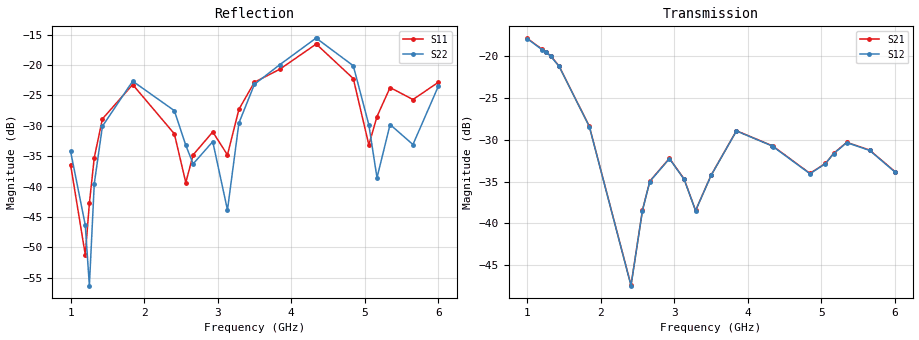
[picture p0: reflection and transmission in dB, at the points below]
!Agilent Technologies,E8364B,MY43040528,A.07.50.67
!Agilent E8364B: A.07.50.67
!Date: Sunday, March 01, 2026 22:01:33
!Correction: S11(Full 2 Port(1,2))
!S21(Full 2 Port(1,2))
!S12(Full 2 Port(1,2))
!S22(Full 2 Port(1,2))
!S2P File: Measurements: S11, S21, S12, S22:
# Hz S  dB  R 50
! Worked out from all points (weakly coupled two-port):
!   451 points, 1 GHz to 6 GHz, reference 50 ohm
!   highest |S21| = -17.88 dB at 1 GHz (marker M1); lowest = -47.4 dB at 2.411 GHz (marker M2)
!   lowest |S11| = -51.2 dB at 1.2 GHz (marker M3), VSWR 1.01, Z = 50.1 - j0.244 ohm
!   |S11| at or under -10 dB: start of sweep to end of sweep
!   |S22| runs from -61.2 to -15.6 dB; largest |S21 - S12| = 0.00051
!   S11 on the Smith chart (normalised r, x): 1 GHz: 1.03, +0.01; 4.333 GHz: 1.23, -0.24; 6 GHz: 0.98, -0.14
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1e9  -36.38 17.3  -17.88 28.8  -17.92 28.9  -34.18 -28.7
1.2e9  -51.20 -62.2  -19.18 -31.3  -19.22 -31.3  -46.32 -34.0
1.255556e9  -42.75 -129.8  -19.50 -49.2  -19.54 -49.2  -56.28 -177.4
1.322222e9  -35.21 -153.7  -20.00 -71.4  -20.04 -71.3  -39.50 128.3
1.433333e9  -28.85 174.5  -21.20 -108.7  -21.23 -108.7  -30.05 95.0
1.844444e9  -23.21 83.4  -28.40 121.9  -28.43 122.0  -22.65 -14.1
2.411111e9  -31.31 5.6  -47.38 -127.2  -47.44 -127.2  -27.50 -123.5
2.566667e9  -39.32 37.0  -38.42 108.8  -38.46 108.9  -33.19 -139.6
2.666667e9  -34.76 71.8  -34.95 63.8  -34.99 63.8  -36.25 -116.7
2.933333e9  -31.00 41.8  -32.22 -42.4  -32.26 -42.3  -32.59 -134.1
3.133333e9  -34.77 73.9  -34.69 -110.6  -34.73 -110.6  -43.83 -105.6
3.288889e9  -27.28 84.6  -38.45 -135.3  -38.48 -135.3  -29.54 -74.6
3.5e9  -22.82 55.1  -34.23 -154.3  -34.27 -154.2  -23.16 -119.4
3.844444e9  -20.69 24.7  -28.92 88.5  -28.95 88.5  -19.94 -169.9
4.333333e9  -16.60 -39.2  -30.72 -86.2  -30.75 -86.1  -15.61 106.3
4.344444e9  -16.59 -40.9  -30.79 -90.2  -30.83 -90.1  -15.61 104.0
4.844444e9  -22.22 -122.8  -34.02 51.1  -34.06 51.1  -20.12 -5.1
5.055556e9  -33.12 -102.6  -32.82 -66.5  -32.85 -66.5  -29.82 -46.1
5.166667e9  -28.47 -61.4  -31.62 -123.6  -31.66 -123.6  -38.53 1.8
5.344444e9  -23.69 -79.0  -30.31 153.7  -30.34 153.7  -29.78 20.1
5.655556e9  -25.67 -102.5  -31.23 28.1  -31.27 28.1  -33.07 10.1
6e9  -22.84 -94.7  -33.81 -69.3  -33.85 -69.3  -23.51 -3.9
